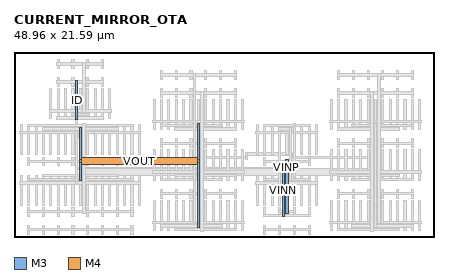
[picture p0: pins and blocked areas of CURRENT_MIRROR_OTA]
MACRO CURRENT_MIRROR_OTA
  ORIGIN 0 0 ;
  FOREIGN CURRENT_MIRROR_OTA 0 0 ;
  SIZE 48.96 BY 21.59 ;
  PIN ID
    DIRECTION INOUT ;
    USE SIGNAL ;
    PORT 
      LAYER M3 ;
        RECT 7.17 13.7 7.45 18.22 ;
    END
  END ID
  PIN VOUT
    DIRECTION INOUT ;
    USE SIGNAL ;
    PORT 
      LAYER M3 ;
        RECT 7.6 6.56 7.88 12.76 ;
      LAYER M3 ;
        RECT 21.36 1.1 21.64 13.18 ;
      LAYER M3 ;
        RECT 7.6 8.635 7.88 9.005 ;
      LAYER M4 ;
        RECT 7.74 8.42 21.5 9.22 ;
      LAYER M3 ;
        RECT 21.36 8.635 21.64 9.005 ;
    END
  END VOUT
  PIN VINP
    DIRECTION INOUT ;
    USE SIGNAL ;
    PORT 
      LAYER M3 ;
        RECT 31.68 2.78 31.96 8.98 ;
    END
  END VINP
  PIN VINN
    DIRECTION INOUT ;
    USE SIGNAL ;
    PORT 
      LAYER M3 ;
        RECT 31.25 2.36 31.53 8.56 ;
    END
  END VINN
  OBS 
  LAYER M3 ;
        RECT 7.17 6.14 7.45 12.34 ;
  LAYER M2 ;
        RECT 6.71 14.14 8.77 14.42 ;
  LAYER M3 ;
        RECT 30.82 6.14 31.1 12.34 ;
  LAYER M3 ;
        RECT 7.17 11.575 7.45 11.945 ;
  LAYER M2 ;
        RECT 7.161 11.62 7.459 11.9 ;
  LAYER M1 ;
        RECT 7.185 11.76 7.435 14.28 ;
  LAYER M2 ;
        RECT 7.15 14.14 7.47 14.42 ;
  LAYER M3 ;
        RECT 7.17 7.795 7.45 8.165 ;
  LAYER M2 ;
        RECT 7.31 7.84 30.96 8.12 ;
  LAYER M3 ;
        RECT 30.82 7.795 31.1 8.165 ;
  LAYER M1 ;
        RECT 7.185 11.675 7.435 11.845 ;
  LAYER M2 ;
        RECT 7.14 11.62 7.48 11.9 ;
  LAYER M1 ;
        RECT 7.185 14.195 7.435 14.365 ;
  LAYER M2 ;
        RECT 7.14 14.14 7.48 14.42 ;
  LAYER M2 ;
        RECT 7.15 11.62 7.47 11.9 ;
  LAYER M3 ;
        RECT 7.17 11.6 7.45 11.92 ;
  LAYER M1 ;
        RECT 7.185 14.195 7.435 14.365 ;
  LAYER M2 ;
        RECT 7.14 14.14 7.48 14.42 ;
  LAYER M1 ;
        RECT 7.185 14.195 7.435 14.365 ;
  LAYER M2 ;
        RECT 7.14 14.14 7.48 14.42 ;
  LAYER M2 ;
        RECT 7.15 7.84 7.47 8.12 ;
  LAYER M3 ;
        RECT 7.17 7.82 7.45 8.14 ;
  LAYER M2 ;
        RECT 30.8 7.84 31.12 8.12 ;
  LAYER M3 ;
        RECT 30.82 7.82 31.1 8.14 ;
  LAYER M1 ;
        RECT 7.185 14.195 7.435 14.365 ;
  LAYER M2 ;
        RECT 7.14 14.14 7.48 14.42 ;
  LAYER M2 ;
        RECT 7.15 7.84 7.47 8.12 ;
  LAYER M3 ;
        RECT 7.17 7.82 7.45 8.14 ;
  LAYER M2 ;
        RECT 30.8 7.84 31.12 8.12 ;
  LAYER M3 ;
        RECT 30.82 7.82 31.1 8.14 ;
  LAYER M3 ;
        RECT 32.54 6.98 32.82 13.18 ;
  LAYER M3 ;
        RECT 41.57 0.68 41.85 16.96 ;
  LAYER M3 ;
        RECT 32.54 9.055 32.82 9.425 ;
  LAYER M2 ;
        RECT 32.68 9.1 41.71 9.38 ;
  LAYER M3 ;
        RECT 41.57 9.055 41.85 9.425 ;
  LAYER M2 ;
        RECT 32.52 9.1 32.84 9.38 ;
  LAYER M3 ;
        RECT 32.54 9.08 32.82 9.4 ;
  LAYER M2 ;
        RECT 41.55 9.1 41.87 9.38 ;
  LAYER M3 ;
        RECT 41.57 9.08 41.85 9.4 ;
  LAYER M2 ;
        RECT 32.52 9.1 32.84 9.38 ;
  LAYER M3 ;
        RECT 32.54 9.08 32.82 9.4 ;
  LAYER M2 ;
        RECT 41.55 9.1 41.87 9.38 ;
  LAYER M3 ;
        RECT 41.57 9.08 41.85 9.4 ;
  LAYER M3 ;
        RECT 8.03 2.78 8.31 13.18 ;
  LAYER M3 ;
        RECT 42 1.1 42.28 13.18 ;
  LAYER M3 ;
        RECT 8.03 7.375 8.31 7.745 ;
  LAYER M4 ;
        RECT 8.17 7.16 42.14 7.96 ;
  LAYER M3 ;
        RECT 42 7.375 42.28 7.745 ;
  LAYER M3 ;
        RECT 8.03 7.375 8.31 7.745 ;
  LAYER M4 ;
        RECT 8.005 7.16 8.335 7.96 ;
  LAYER M3 ;
        RECT 42 7.375 42.28 7.745 ;
  LAYER M4 ;
        RECT 41.975 7.16 42.305 7.96 ;
  LAYER M3 ;
        RECT 8.03 7.375 8.31 7.745 ;
  LAYER M4 ;
        RECT 8.005 7.16 8.335 7.96 ;
  LAYER M3 ;
        RECT 42 7.375 42.28 7.745 ;
  LAYER M4 ;
        RECT 41.975 7.16 42.305 7.96 ;
  LAYER M3 ;
        RECT 32.11 6.56 32.39 12.76 ;
  LAYER M3 ;
        RECT 21.79 0.68 22.07 16.96 ;
  LAYER M3 ;
        RECT 32.11 9.475 32.39 9.845 ;
  LAYER M2 ;
        RECT 27.09 9.52 32.25 9.8 ;
  LAYER M3 ;
        RECT 26.95 9.24 27.23 9.66 ;
  LAYER M2 ;
        RECT 21.93 9.1 27.09 9.38 ;
  LAYER M3 ;
        RECT 21.79 9.055 22.07 9.425 ;
  LAYER M2 ;
        RECT 21.77 9.1 22.09 9.38 ;
  LAYER M3 ;
        RECT 21.79 9.08 22.07 9.4 ;
  LAYER M2 ;
        RECT 26.93 9.1 27.25 9.38 ;
  LAYER M3 ;
        RECT 26.95 9.08 27.23 9.4 ;
  LAYER M2 ;
        RECT 26.93 9.52 27.25 9.8 ;
  LAYER M3 ;
        RECT 26.95 9.5 27.23 9.82 ;
  LAYER M2 ;
        RECT 32.09 9.52 32.41 9.8 ;
  LAYER M3 ;
        RECT 32.11 9.5 32.39 9.82 ;
  LAYER M2 ;
        RECT 21.77 9.1 22.09 9.38 ;
  LAYER M3 ;
        RECT 21.79 9.08 22.07 9.4 ;
  LAYER M2 ;
        RECT 26.93 9.1 27.25 9.38 ;
  LAYER M3 ;
        RECT 26.95 9.08 27.23 9.4 ;
  LAYER M2 ;
        RECT 26.93 9.52 27.25 9.8 ;
  LAYER M3 ;
        RECT 26.95 9.5 27.23 9.82 ;
  LAYER M2 ;
        RECT 32.09 9.52 32.41 9.8 ;
  LAYER M3 ;
        RECT 32.11 9.5 32.39 9.82 ;
  LAYER M1 ;
        RECT 5.035 13.775 5.285 17.305 ;
  LAYER M1 ;
        RECT 5.035 17.555 5.285 18.565 ;
  LAYER M1 ;
        RECT 5.035 19.655 5.285 20.665 ;
  LAYER M1 ;
        RECT 4.175 13.775 4.425 17.305 ;
  LAYER M1 ;
        RECT 5.895 13.775 6.145 17.305 ;
  LAYER M1 ;
        RECT 6.755 13.775 7.005 17.305 ;
  LAYER M1 ;
        RECT 6.755 17.555 7.005 18.565 ;
  LAYER M1 ;
        RECT 6.755 19.655 7.005 20.665 ;
  LAYER M1 ;
        RECT 7.615 13.775 7.865 17.305 ;
  LAYER M1 ;
        RECT 8.475 13.775 8.725 17.305 ;
  LAYER M1 ;
        RECT 8.475 17.555 8.725 18.565 ;
  LAYER M1 ;
        RECT 8.475 19.655 8.725 20.665 ;
  LAYER M1 ;
        RECT 9.335 13.775 9.585 17.305 ;
  LAYER M1 ;
        RECT 10.195 13.775 10.445 17.305 ;
  LAYER M1 ;
        RECT 10.195 17.555 10.445 18.565 ;
  LAYER M1 ;
        RECT 10.195 19.655 10.445 20.665 ;
  LAYER M1 ;
        RECT 11.055 13.775 11.305 17.305 ;
  LAYER M2 ;
        RECT 4.99 13.72 10.49 14 ;
  LAYER M2 ;
        RECT 4.99 17.92 10.49 18.2 ;
  LAYER M2 ;
        RECT 4.99 20.02 10.49 20.3 ;
  LAYER M2 ;
        RECT 4.13 14.56 11.35 14.84 ;
  LAYER M3 ;
        RECT 7.17 13.7 7.45 18.22 ;
  LAYER M2 ;
        RECT 6.71 14.14 8.77 14.42 ;
  LAYER M3 ;
        RECT 8.03 14.54 8.31 20.32 ;
  LAYER M1 ;
        RECT 37.715 0.755 37.965 4.285 ;
  LAYER M1 ;
        RECT 37.715 4.535 37.965 5.545 ;
  LAYER M1 ;
        RECT 37.715 6.635 37.965 10.165 ;
  LAYER M1 ;
        RECT 37.715 10.415 37.965 11.425 ;
  LAYER M1 ;
        RECT 37.715 12.515 37.965 16.045 ;
  LAYER M1 ;
        RECT 37.715 16.295 37.965 17.305 ;
  LAYER M1 ;
        RECT 37.715 18.395 37.965 19.405 ;
  LAYER M1 ;
        RECT 36.855 0.755 37.105 4.285 ;
  LAYER M1 ;
        RECT 36.855 6.635 37.105 10.165 ;
  LAYER M1 ;
        RECT 36.855 12.515 37.105 16.045 ;
  LAYER M1 ;
        RECT 38.575 0.755 38.825 4.285 ;
  LAYER M1 ;
        RECT 38.575 6.635 38.825 10.165 ;
  LAYER M1 ;
        RECT 38.575 12.515 38.825 16.045 ;
  LAYER M1 ;
        RECT 39.435 0.755 39.685 4.285 ;
  LAYER M1 ;
        RECT 39.435 4.535 39.685 5.545 ;
  LAYER M1 ;
        RECT 39.435 6.635 39.685 10.165 ;
  LAYER M1 ;
        RECT 39.435 10.415 39.685 11.425 ;
  LAYER M1 ;
        RECT 39.435 12.515 39.685 16.045 ;
  LAYER M1 ;
        RECT 39.435 16.295 39.685 17.305 ;
  LAYER M1 ;
        RECT 39.435 18.395 39.685 19.405 ;
  LAYER M1 ;
        RECT 40.295 0.755 40.545 4.285 ;
  LAYER M1 ;
        RECT 40.295 6.635 40.545 10.165 ;
  LAYER M1 ;
        RECT 40.295 12.515 40.545 16.045 ;
  LAYER M1 ;
        RECT 41.155 0.755 41.405 4.285 ;
  LAYER M1 ;
        RECT 41.155 4.535 41.405 5.545 ;
  LAYER M1 ;
        RECT 41.155 6.635 41.405 10.165 ;
  LAYER M1 ;
        RECT 41.155 10.415 41.405 11.425 ;
  LAYER M1 ;
        RECT 41.155 12.515 41.405 16.045 ;
  LAYER M1 ;
        RECT 41.155 16.295 41.405 17.305 ;
  LAYER M1 ;
        RECT 41.155 18.395 41.405 19.405 ;
  LAYER M1 ;
        RECT 42.015 0.755 42.265 4.285 ;
  LAYER M1 ;
        RECT 42.015 6.635 42.265 10.165 ;
  LAYER M1 ;
        RECT 42.015 12.515 42.265 16.045 ;
  LAYER M1 ;
        RECT 42.875 0.755 43.125 4.285 ;
  LAYER M1 ;
        RECT 42.875 4.535 43.125 5.545 ;
  LAYER M1 ;
        RECT 42.875 6.635 43.125 10.165 ;
  LAYER M1 ;
        RECT 42.875 10.415 43.125 11.425 ;
  LAYER M1 ;
        RECT 42.875 12.515 43.125 16.045 ;
  LAYER M1 ;
        RECT 42.875 16.295 43.125 17.305 ;
  LAYER M1 ;
        RECT 42.875 18.395 43.125 19.405 ;
  LAYER M1 ;
        RECT 43.735 0.755 43.985 4.285 ;
  LAYER M1 ;
        RECT 43.735 6.635 43.985 10.165 ;
  LAYER M1 ;
        RECT 43.735 12.515 43.985 16.045 ;
  LAYER M1 ;
        RECT 44.595 0.755 44.845 4.285 ;
  LAYER M1 ;
        RECT 44.595 4.535 44.845 5.545 ;
  LAYER M1 ;
        RECT 44.595 6.635 44.845 10.165 ;
  LAYER M1 ;
        RECT 44.595 10.415 44.845 11.425 ;
  LAYER M1 ;
        RECT 44.595 12.515 44.845 16.045 ;
  LAYER M1 ;
        RECT 44.595 16.295 44.845 17.305 ;
  LAYER M1 ;
        RECT 44.595 18.395 44.845 19.405 ;
  LAYER M1 ;
        RECT 45.455 0.755 45.705 4.285 ;
  LAYER M1 ;
        RECT 45.455 6.635 45.705 10.165 ;
  LAYER M1 ;
        RECT 45.455 12.515 45.705 16.045 ;
  LAYER M1 ;
        RECT 46.315 0.755 46.565 4.285 ;
  LAYER M1 ;
        RECT 46.315 4.535 46.565 5.545 ;
  LAYER M1 ;
        RECT 46.315 6.635 46.565 10.165 ;
  LAYER M1 ;
        RECT 46.315 10.415 46.565 11.425 ;
  LAYER M1 ;
        RECT 46.315 12.515 46.565 16.045 ;
  LAYER M1 ;
        RECT 46.315 16.295 46.565 17.305 ;
  LAYER M1 ;
        RECT 46.315 18.395 46.565 19.405 ;
  LAYER M1 ;
        RECT 47.175 0.755 47.425 4.285 ;
  LAYER M1 ;
        RECT 47.175 6.635 47.425 10.165 ;
  LAYER M1 ;
        RECT 47.175 12.515 47.425 16.045 ;
  LAYER M2 ;
        RECT 37.67 0.7 44.89 0.98 ;
  LAYER M2 ;
        RECT 37.67 4.9 46.61 5.18 ;
  LAYER M2 ;
        RECT 39.39 1.12 46.61 1.4 ;
  LAYER M2 ;
        RECT 36.81 1.54 47.47 1.82 ;
  LAYER M2 ;
        RECT 39.39 6.58 46.61 6.86 ;
  LAYER M2 ;
        RECT 37.67 10.78 46.61 11.06 ;
  LAYER M2 ;
        RECT 37.67 7 44.89 7.28 ;
  LAYER M2 ;
        RECT 36.81 7.42 47.47 7.7 ;
  LAYER M2 ;
        RECT 37.67 12.46 44.89 12.74 ;
  LAYER M2 ;
        RECT 37.67 16.66 46.61 16.94 ;
  LAYER M2 ;
        RECT 39.39 12.88 46.61 13.16 ;
  LAYER M2 ;
        RECT 37.67 18.76 46.61 19.04 ;
  LAYER M2 ;
        RECT 36.81 13.3 47.47 13.58 ;
  LAYER M3 ;
        RECT 41.57 0.68 41.85 16.96 ;
  LAYER M3 ;
        RECT 42 1.1 42.28 13.18 ;
  LAYER M3 ;
        RECT 42.43 1.52 42.71 19.06 ;
  LAYER M1 ;
        RECT 25.675 0.755 25.925 4.285 ;
  LAYER M1 ;
        RECT 25.675 4.535 25.925 5.545 ;
  LAYER M1 ;
        RECT 25.675 6.635 25.925 10.165 ;
  LAYER M1 ;
        RECT 25.675 10.415 25.925 11.425 ;
  LAYER M1 ;
        RECT 25.675 12.515 25.925 16.045 ;
  LAYER M1 ;
        RECT 25.675 16.295 25.925 17.305 ;
  LAYER M1 ;
        RECT 25.675 18.395 25.925 19.405 ;
  LAYER M1 ;
        RECT 26.535 0.755 26.785 4.285 ;
  LAYER M1 ;
        RECT 26.535 6.635 26.785 10.165 ;
  LAYER M1 ;
        RECT 26.535 12.515 26.785 16.045 ;
  LAYER M1 ;
        RECT 24.815 0.755 25.065 4.285 ;
  LAYER M1 ;
        RECT 24.815 6.635 25.065 10.165 ;
  LAYER M1 ;
        RECT 24.815 12.515 25.065 16.045 ;
  LAYER M1 ;
        RECT 23.955 0.755 24.205 4.285 ;
  LAYER M1 ;
        RECT 23.955 4.535 24.205 5.545 ;
  LAYER M1 ;
        RECT 23.955 6.635 24.205 10.165 ;
  LAYER M1 ;
        RECT 23.955 10.415 24.205 11.425 ;
  LAYER M1 ;
        RECT 23.955 12.515 24.205 16.045 ;
  LAYER M1 ;
        RECT 23.955 16.295 24.205 17.305 ;
  LAYER M1 ;
        RECT 23.955 18.395 24.205 19.405 ;
  LAYER M1 ;
        RECT 23.095 0.755 23.345 4.285 ;
  LAYER M1 ;
        RECT 23.095 6.635 23.345 10.165 ;
  LAYER M1 ;
        RECT 23.095 12.515 23.345 16.045 ;
  LAYER M1 ;
        RECT 22.235 0.755 22.485 4.285 ;
  LAYER M1 ;
        RECT 22.235 4.535 22.485 5.545 ;
  LAYER M1 ;
        RECT 22.235 6.635 22.485 10.165 ;
  LAYER M1 ;
        RECT 22.235 10.415 22.485 11.425 ;
  LAYER M1 ;
        RECT 22.235 12.515 22.485 16.045 ;
  LAYER M1 ;
        RECT 22.235 16.295 22.485 17.305 ;
  LAYER M1 ;
        RECT 22.235 18.395 22.485 19.405 ;
  LAYER M1 ;
        RECT 21.375 0.755 21.625 4.285 ;
  LAYER M1 ;
        RECT 21.375 6.635 21.625 10.165 ;
  LAYER M1 ;
        RECT 21.375 12.515 21.625 16.045 ;
  LAYER M1 ;
        RECT 20.515 0.755 20.765 4.285 ;
  LAYER M1 ;
        RECT 20.515 4.535 20.765 5.545 ;
  LAYER M1 ;
        RECT 20.515 6.635 20.765 10.165 ;
  LAYER M1 ;
        RECT 20.515 10.415 20.765 11.425 ;
  LAYER M1 ;
        RECT 20.515 12.515 20.765 16.045 ;
  LAYER M1 ;
        RECT 20.515 16.295 20.765 17.305 ;
  LAYER M1 ;
        RECT 20.515 18.395 20.765 19.405 ;
  LAYER M1 ;
        RECT 19.655 0.755 19.905 4.285 ;
  LAYER M1 ;
        RECT 19.655 6.635 19.905 10.165 ;
  LAYER M1 ;
        RECT 19.655 12.515 19.905 16.045 ;
  LAYER M1 ;
        RECT 18.795 0.755 19.045 4.285 ;
  LAYER M1 ;
        RECT 18.795 4.535 19.045 5.545 ;
  LAYER M1 ;
        RECT 18.795 6.635 19.045 10.165 ;
  LAYER M1 ;
        RECT 18.795 10.415 19.045 11.425 ;
  LAYER M1 ;
        RECT 18.795 12.515 19.045 16.045 ;
  LAYER M1 ;
        RECT 18.795 16.295 19.045 17.305 ;
  LAYER M1 ;
        RECT 18.795 18.395 19.045 19.405 ;
  LAYER M1 ;
        RECT 17.935 0.755 18.185 4.285 ;
  LAYER M1 ;
        RECT 17.935 6.635 18.185 10.165 ;
  LAYER M1 ;
        RECT 17.935 12.515 18.185 16.045 ;
  LAYER M1 ;
        RECT 17.075 0.755 17.325 4.285 ;
  LAYER M1 ;
        RECT 17.075 4.535 17.325 5.545 ;
  LAYER M1 ;
        RECT 17.075 6.635 17.325 10.165 ;
  LAYER M1 ;
        RECT 17.075 10.415 17.325 11.425 ;
  LAYER M1 ;
        RECT 17.075 12.515 17.325 16.045 ;
  LAYER M1 ;
        RECT 17.075 16.295 17.325 17.305 ;
  LAYER M1 ;
        RECT 17.075 18.395 17.325 19.405 ;
  LAYER M1 ;
        RECT 16.215 0.755 16.465 4.285 ;
  LAYER M1 ;
        RECT 16.215 6.635 16.465 10.165 ;
  LAYER M1 ;
        RECT 16.215 12.515 16.465 16.045 ;
  LAYER M2 ;
        RECT 18.75 0.7 25.97 0.98 ;
  LAYER M2 ;
        RECT 17.03 4.9 25.97 5.18 ;
  LAYER M2 ;
        RECT 17.03 1.12 24.25 1.4 ;
  LAYER M2 ;
        RECT 16.17 1.54 26.83 1.82 ;
  LAYER M2 ;
        RECT 17.03 6.58 24.25 6.86 ;
  LAYER M2 ;
        RECT 17.03 10.78 25.97 11.06 ;
  LAYER M2 ;
        RECT 18.75 7 25.97 7.28 ;
  LAYER M2 ;
        RECT 16.17 7.42 26.83 7.7 ;
  LAYER M2 ;
        RECT 18.75 12.46 25.97 12.74 ;
  LAYER M2 ;
        RECT 17.03 16.66 25.97 16.94 ;
  LAYER M2 ;
        RECT 17.03 12.88 24.25 13.16 ;
  LAYER M2 ;
        RECT 17.03 18.76 25.97 19.04 ;
  LAYER M2 ;
        RECT 16.17 13.3 26.83 13.58 ;
  LAYER M3 ;
        RECT 21.79 0.68 22.07 16.96 ;
  LAYER M3 ;
        RECT 21.36 1.1 21.64 13.18 ;
  LAYER M3 ;
        RECT 20.93 1.52 21.21 19.06 ;
  LAYER M1 ;
        RECT 13.635 9.575 13.885 13.105 ;
  LAYER M1 ;
        RECT 13.635 8.315 13.885 9.325 ;
  LAYER M1 ;
        RECT 13.635 3.695 13.885 7.225 ;
  LAYER M1 ;
        RECT 13.635 2.435 13.885 3.445 ;
  LAYER M1 ;
        RECT 13.635 0.335 13.885 1.345 ;
  LAYER M1 ;
        RECT 14.495 9.575 14.745 13.105 ;
  LAYER M1 ;
        RECT 14.495 3.695 14.745 7.225 ;
  LAYER M1 ;
        RECT 12.775 9.575 13.025 13.105 ;
  LAYER M1 ;
        RECT 12.775 3.695 13.025 7.225 ;
  LAYER M1 ;
        RECT 11.915 9.575 12.165 13.105 ;
  LAYER M1 ;
        RECT 11.915 8.315 12.165 9.325 ;
  LAYER M1 ;
        RECT 11.915 3.695 12.165 7.225 ;
  LAYER M1 ;
        RECT 11.915 2.435 12.165 3.445 ;
  LAYER M1 ;
        RECT 11.915 0.335 12.165 1.345 ;
  LAYER M1 ;
        RECT 11.055 9.575 11.305 13.105 ;
  LAYER M1 ;
        RECT 11.055 3.695 11.305 7.225 ;
  LAYER M1 ;
        RECT 10.195 9.575 10.445 13.105 ;
  LAYER M1 ;
        RECT 10.195 8.315 10.445 9.325 ;
  LAYER M1 ;
        RECT 10.195 3.695 10.445 7.225 ;
  LAYER M1 ;
        RECT 10.195 2.435 10.445 3.445 ;
  LAYER M1 ;
        RECT 10.195 0.335 10.445 1.345 ;
  LAYER M1 ;
        RECT 9.335 9.575 9.585 13.105 ;
  LAYER M1 ;
        RECT 9.335 3.695 9.585 7.225 ;
  LAYER M1 ;
        RECT 8.475 9.575 8.725 13.105 ;
  LAYER M1 ;
        RECT 8.475 8.315 8.725 9.325 ;
  LAYER M1 ;
        RECT 8.475 3.695 8.725 7.225 ;
  LAYER M1 ;
        RECT 8.475 2.435 8.725 3.445 ;
  LAYER M1 ;
        RECT 8.475 0.335 8.725 1.345 ;
  LAYER M1 ;
        RECT 7.615 9.575 7.865 13.105 ;
  LAYER M1 ;
        RECT 7.615 3.695 7.865 7.225 ;
  LAYER M1 ;
        RECT 6.755 9.575 7.005 13.105 ;
  LAYER M1 ;
        RECT 6.755 8.315 7.005 9.325 ;
  LAYER M1 ;
        RECT 6.755 3.695 7.005 7.225 ;
  LAYER M1 ;
        RECT 6.755 2.435 7.005 3.445 ;
  LAYER M1 ;
        RECT 6.755 0.335 7.005 1.345 ;
  LAYER M1 ;
        RECT 5.895 9.575 6.145 13.105 ;
  LAYER M1 ;
        RECT 5.895 3.695 6.145 7.225 ;
  LAYER M1 ;
        RECT 5.035 9.575 5.285 13.105 ;
  LAYER M1 ;
        RECT 5.035 8.315 5.285 9.325 ;
  LAYER M1 ;
        RECT 5.035 3.695 5.285 7.225 ;
  LAYER M1 ;
        RECT 5.035 2.435 5.285 3.445 ;
  LAYER M1 ;
        RECT 5.035 0.335 5.285 1.345 ;
  LAYER M1 ;
        RECT 4.175 9.575 4.425 13.105 ;
  LAYER M1 ;
        RECT 4.175 3.695 4.425 7.225 ;
  LAYER M1 ;
        RECT 3.315 9.575 3.565 13.105 ;
  LAYER M1 ;
        RECT 3.315 8.315 3.565 9.325 ;
  LAYER M1 ;
        RECT 3.315 3.695 3.565 7.225 ;
  LAYER M1 ;
        RECT 3.315 2.435 3.565 3.445 ;
  LAYER M1 ;
        RECT 3.315 0.335 3.565 1.345 ;
  LAYER M1 ;
        RECT 2.455 9.575 2.705 13.105 ;
  LAYER M1 ;
        RECT 2.455 3.695 2.705 7.225 ;
  LAYER M1 ;
        RECT 1.595 9.575 1.845 13.105 ;
  LAYER M1 ;
        RECT 1.595 8.315 1.845 9.325 ;
  LAYER M1 ;
        RECT 1.595 3.695 1.845 7.225 ;
  LAYER M1 ;
        RECT 1.595 2.435 1.845 3.445 ;
  LAYER M1 ;
        RECT 1.595 0.335 1.845 1.345 ;
  LAYER M1 ;
        RECT 0.735 9.575 0.985 13.105 ;
  LAYER M1 ;
        RECT 0.735 3.695 0.985 7.225 ;
  LAYER M2 ;
        RECT 1.55 12.88 13.93 13.16 ;
  LAYER M2 ;
        RECT 1.55 8.68 13.93 8.96 ;
  LAYER M2 ;
        RECT 3.27 12.46 12.21 12.74 ;
  LAYER M2 ;
        RECT 0.69 12.04 14.79 12.32 ;
  LAYER M2 ;
        RECT 3.27 7 12.21 7.28 ;
  LAYER M2 ;
        RECT 1.55 2.8 13.93 3.08 ;
  LAYER M2 ;
        RECT 1.55 6.58 13.93 6.86 ;
  LAYER M2 ;
        RECT 0.69 6.16 14.79 6.44 ;
  LAYER M2 ;
        RECT 1.55 0.7 13.93 0.98 ;
  LAYER M3 ;
        RECT 8.03 2.78 8.31 13.18 ;
  LAYER M3 ;
        RECT 7.6 6.56 7.88 12.76 ;
  LAYER M3 ;
        RECT 7.17 6.14 7.45 12.34 ;
  LAYER M1 ;
        RECT 34.275 9.575 34.525 13.105 ;
  LAYER M1 ;
        RECT 34.275 8.315 34.525 9.325 ;
  LAYER M1 ;
        RECT 34.275 3.695 34.525 7.225 ;
  LAYER M1 ;
        RECT 34.275 2.435 34.525 3.445 ;
  LAYER M1 ;
        RECT 34.275 0.335 34.525 1.345 ;
  LAYER M1 ;
        RECT 35.135 9.575 35.385 13.105 ;
  LAYER M1 ;
        RECT 35.135 3.695 35.385 7.225 ;
  LAYER M1 ;
        RECT 33.415 9.575 33.665 13.105 ;
  LAYER M1 ;
        RECT 33.415 3.695 33.665 7.225 ;
  LAYER M1 ;
        RECT 32.555 9.575 32.805 13.105 ;
  LAYER M1 ;
        RECT 32.555 8.315 32.805 9.325 ;
  LAYER M1 ;
        RECT 32.555 3.695 32.805 7.225 ;
  LAYER M1 ;
        RECT 32.555 2.435 32.805 3.445 ;
  LAYER M1 ;
        RECT 32.555 0.335 32.805 1.345 ;
  LAYER M1 ;
        RECT 31.695 9.575 31.945 13.105 ;
  LAYER M1 ;
        RECT 31.695 3.695 31.945 7.225 ;
  LAYER M1 ;
        RECT 30.835 9.575 31.085 13.105 ;
  LAYER M1 ;
        RECT 30.835 8.315 31.085 9.325 ;
  LAYER M1 ;
        RECT 30.835 3.695 31.085 7.225 ;
  LAYER M1 ;
        RECT 30.835 2.435 31.085 3.445 ;
  LAYER M1 ;
        RECT 30.835 0.335 31.085 1.345 ;
  LAYER M1 ;
        RECT 29.975 9.575 30.225 13.105 ;
  LAYER M1 ;
        RECT 29.975 3.695 30.225 7.225 ;
  LAYER M1 ;
        RECT 29.115 9.575 29.365 13.105 ;
  LAYER M1 ;
        RECT 29.115 8.315 29.365 9.325 ;
  LAYER M1 ;
        RECT 29.115 3.695 29.365 7.225 ;
  LAYER M1 ;
        RECT 29.115 2.435 29.365 3.445 ;
  LAYER M1 ;
        RECT 29.115 0.335 29.365 1.345 ;
  LAYER M1 ;
        RECT 28.255 9.575 28.505 13.105 ;
  LAYER M1 ;
        RECT 28.255 3.695 28.505 7.225 ;
  LAYER M2 ;
        RECT 29.07 12.88 34.57 13.16 ;
  LAYER M2 ;
        RECT 30.79 12.46 32.85 12.74 ;
  LAYER M2 ;
        RECT 29.07 8.68 34.57 8.96 ;
  LAYER M2 ;
        RECT 30.79 8.26 32.85 8.54 ;
  LAYER M2 ;
        RECT 28.21 12.04 35.43 12.32 ;
  LAYER M2 ;
        RECT 30.79 7 32.85 7.28 ;
  LAYER M2 ;
        RECT 29.07 6.58 34.57 6.86 ;
  LAYER M2 ;
        RECT 30.79 2.8 32.85 3.08 ;
  LAYER M2 ;
        RECT 29.07 2.38 34.57 2.66 ;
  LAYER M2 ;
        RECT 28.21 6.16 35.43 6.44 ;
  LAYER M2 ;
        RECT 29.07 0.7 34.57 0.98 ;
  LAYER M3 ;
        RECT 32.54 6.98 32.82 13.18 ;
  LAYER M3 ;
        RECT 32.11 6.56 32.39 12.76 ;
  LAYER M3 ;
        RECT 31.68 2.78 31.96 8.98 ;
  LAYER M3 ;
        RECT 31.25 2.36 31.53 8.56 ;
  LAYER M3 ;
        RECT 30.82 6.14 31.1 12.34 ;
  END 
END CURRENT_MIRROR_OTA
